VERSION 5.8 ;
BUSBITCHARS "[]" ;
DIVIDERCHAR "/" ;
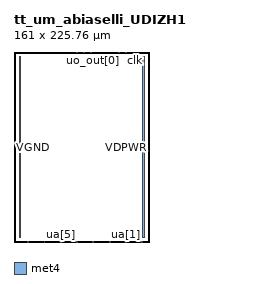
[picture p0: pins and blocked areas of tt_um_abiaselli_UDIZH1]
MACRO tt_um_abiaselli_UDIZH1
  CLASS BLOCK ;
  FOREIGN tt_um_abiaselli_UDIZH1 0 0 ;
  ORIGIN 0 0 ;
  SIZE 161.000 BY 225.760 ;
  SYMMETRY X Y R90 ;
  SITE unithd ;
  PIN clk
    DIRECTION INPUT ;
    USE SIGNAL ;
    PORT
      LAYER met4 ;
        RECT 143.830 224.760 144.130 225.760 ;
    END
  END clk
  PIN ena
    DIRECTION INPUT ;
    USE SIGNAL ;
    PORT
      LAYER met4 ;
        RECT 146.590 224.760 146.890 225.760 ;
    END
  END ena
  PIN rst_n
    DIRECTION INPUT ;
    USE SIGNAL ;
    PORT
      LAYER met4 ;
        RECT 141.070 224.760 141.370 225.760 ;
    END
  END rst_n
  PIN ua[0]
    DIRECTION INOUT ;
    USE SIGNAL ;
    PORT
      LAYER met4 ;
        RECT 151.810 0.000 152.710 1.000 ;
    END
  END ua[0]
  PIN ua[1]
    DIRECTION INOUT ;
    USE SIGNAL ;
    PORT
      LAYER met4 ;
        RECT 132.490 0.000 133.390 1.000 ;
    END
  END ua[1]
  PIN ua[2]
    DIRECTION INOUT ;
    USE SIGNAL ;
    PORT
      LAYER met4 ;
        RECT 113.170 0.000 114.070 1.000 ;
    END
  END ua[2]
  PIN ua[3]
    DIRECTION INOUT ;
    USE SIGNAL ;
    PORT
      LAYER met4 ;
        RECT 93.850 0.000 94.750 1.000 ;
    END
  END ua[3]
  PIN ua[4]
    DIRECTION INOUT ;
    USE SIGNAL ;
    PORT
      LAYER met4 ;
        RECT 74.530 0.000 75.430 1.000 ;
    END
  END ua[4]
  PIN ua[5]
    DIRECTION INOUT ;
    USE SIGNAL ;
    PORT
      LAYER met4 ;
        RECT 55.210 0.000 56.110 1.000 ;
    END
  END ua[5]
  PIN ua[6]
    DIRECTION INOUT ;
    USE SIGNAL ;
    PORT
      LAYER met4 ;
        RECT 35.890 0.000 36.790 1.000 ;
    END
  END ua[6]
  PIN ua[7]
    DIRECTION INOUT ;
    USE SIGNAL ;
    PORT
      LAYER met4 ;
        RECT 16.570 0.000 17.470 1.000 ;
    END
  END ua[7]
  PIN ui_in[0]
    DIRECTION INPUT ;
    USE SIGNAL ;
    PORT
      LAYER met4 ;
        RECT 138.310 224.760 138.610 225.760 ;
    END
  END ui_in[0]
  PIN ui_in[1]
    DIRECTION INPUT ;
    USE SIGNAL ;
    PORT
      LAYER met4 ;
        RECT 135.550 224.760 135.850 225.760 ;
    END
  END ui_in[1]
  PIN ui_in[2]
    DIRECTION INPUT ;
    USE SIGNAL ;
    PORT
      LAYER met4 ;
        RECT 132.790 224.760 133.090 225.760 ;
    END
  END ui_in[2]
  PIN ui_in[3]
    DIRECTION INPUT ;
    USE SIGNAL ;
    PORT
      LAYER met4 ;
        RECT 130.030 224.760 130.330 225.760 ;
    END
  END ui_in[3]
  PIN ui_in[4]
    DIRECTION INPUT ;
    USE SIGNAL ;
    PORT
      LAYER met4 ;
        RECT 127.270 224.760 127.570 225.760 ;
    END
  END ui_in[4]
  PIN ui_in[5]
    DIRECTION INPUT ;
    USE SIGNAL ;
    PORT
      LAYER met4 ;
        RECT 124.510 224.760 124.810 225.760 ;
    END
  END ui_in[5]
  PIN ui_in[6]
    DIRECTION INPUT ;
    USE SIGNAL ;
    PORT
      LAYER met4 ;
        RECT 121.750 224.760 122.050 225.760 ;
    END
  END ui_in[6]
  PIN ui_in[7]
    DIRECTION INPUT ;
    USE SIGNAL ;
    PORT
      LAYER met4 ;
        RECT 118.990 224.760 119.290 225.760 ;
    END
  END ui_in[7]
  PIN uo_out[0]
    DIRECTION OUTPUT ;
    USE SIGNAL ;
    PORT
      LAYER met4 ;
        RECT 94.150 224.760 94.450 225.760 ;
    END
  END uo_out[0]
  PIN uo_out[1]
    DIRECTION OUTPUT ;
    USE SIGNAL ;
    PORT
      LAYER met4 ;
        RECT 91.390 224.760 91.690 225.760 ;
    END
  END uo_out[1]
  PIN uo_out[2]
    DIRECTION OUTPUT ;
    USE SIGNAL ;
    PORT
      LAYER met4 ;
        RECT 88.630 224.760 88.930 225.760 ;
    END
  END uo_out[2]
  PIN uo_out[3]
    DIRECTION OUTPUT ;
    USE SIGNAL ;
    PORT
      LAYER met4 ;
        RECT 85.870 224.760 86.170 225.760 ;
    END
  END uo_out[3]
  PIN uo_out[4]
    DIRECTION OUTPUT ;
    USE SIGNAL ;
    PORT
      LAYER met4 ;
        RECT 83.110 224.760 83.410 225.760 ;
    END
  END uo_out[4]
  PIN uo_out[5]
    DIRECTION OUTPUT ;
    USE SIGNAL ;
    PORT
      LAYER met4 ;
        RECT 80.350 224.760 80.650 225.760 ;
    END
  END uo_out[5]
  PIN uo_out[6]
    DIRECTION OUTPUT ;
    USE SIGNAL ;
    PORT
      LAYER met4 ;
        RECT 77.590 224.760 77.890 225.760 ;
    END
  END uo_out[6]
  PIN uo_out[7]
    DIRECTION OUTPUT ;
    USE SIGNAL ;
    PORT
      LAYER met4 ;
        RECT 74.830 224.760 75.130 225.760 ;
    END
  END uo_out[7]
  PIN VGND
    DIRECTION INOUT ;
    USE GROUND ;
    PORT
      LAYER met4 ;
        RECT 6.000 5.000 8.000 220.760 ;
    END
  END VGND
  PIN VDPWR
    DIRECTION INOUT ;
    USE POWER ;
    PORT
      LAYER met4 ;
        RECT 153.000 5.000 155.000 220.760 ;
    END
  END VDPWR
END tt_um_abiaselli_UDIZH1
END LIBRARY
